VERSION 5.8 ;
BUSBITCHARS "[]" ;
DIVIDERCHAR "/" ;
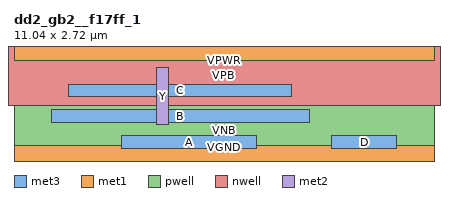
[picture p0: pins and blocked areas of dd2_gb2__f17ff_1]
MACRO dd2_gb2__f17ff_1
  CLASS CORE ;
  ORIGIN 0 0 ;
  SIZE 11.040 BY 2.720 ;
  SYMMETRY X Y ;
  SITE unithd ;
  PIN A
    DIRECTION INPUT ;
    USE SIGNAL ;
    ANTENNAGATEAREA 0.426000 ;
    PORT
      LAYER met3 ;
        RECT 2.825 0.175 6.375 0.505 ;
    END
  END A
  PIN B
    DIRECTION INPUT ;
    USE SIGNAL ;
    ANTENNAGATEAREA 0.426000 ;
    PORT
      LAYER met3 ;
        RECT 0.985 0.855 7.755 1.185 ;
    END
  END B
  PIN C
    DIRECTION INPUT ;
    USE SIGNAL ;
    ANTENNAGATEAREA 0.213000 ;
    PORT
      LAYER met3 ;
        RECT 1.445 1.535 7.295 1.865 ;
    END
  END C
  PIN D
    DIRECTION INPUT ;
    USE SIGNAL ;
    ANTENNAGATEAREA 0.213000 ;
    PORT
      LAYER met3 ;
        RECT 8.345 0.175 10.055 0.505 ;
    END
  END D
  PIN VGND
    DIRECTION INOUT ;
    USE GROUND ;
    SHAPE ABUTMENT ;
    PORT
      LAYER met1 ;
        RECT 0.000 -0.240 11.040 0.240 ;
    END
  END VGND
  PIN VNB
    DIRECTION INOUT ;
    USE GROUND ;
    PORT
      LAYER pwell ;
        RECT 0.000 0.000 11.040 1.305 ;
    END
  END VNB
  PIN VPB
    DIRECTION INOUT ;
    USE POWER ;
    PORT
      LAYER nwell ;
        RECT -0.190 1.305 11.230 2.910 ;
    END
  END VPB
  PIN VPWR
    DIRECTION INOUT ;
    USE POWER ;
    SHAPE ABUTMENT ;
    PORT
      LAYER met1 ;
        RECT 0.000 2.480 11.040 2.960 ;
    END
  END VPWR
  PIN Y
    DIRECTION OUTPUT ;
    USE SIGNAL ;
    ANTENNADIFFAREA 2.635800 ;
    PORT
      LAYER met2 ;
        RECT 3.750 0.790 4.070 2.305 ;
    END
  END Y
  OBS
    LAYER li1 ;
      RECT 0.000 -0.085 11.040 0.085 ;
      RECT 0.605 0.085 0.775 0.565 ;
      RECT 3.365 0.085 3.535 0.565 ;
      RECT 1.905 0.255 2.235 0.710 ;
      RECT 6.505 0.255 6.835 0.710 ;
      RECT 7.885 0.255 8.215 0.710 ;
      RECT 8.805 0.255 9.135 0.710 ;
      RECT 10.185 0.255 10.515 0.710 ;
      RECT 1.065 0.380 1.235 1.075 ;
      RECT 0.945 1.075 1.275 1.245 ;
      RECT 2.905 0.380 3.075 1.075 ;
      RECT 2.785 1.075 3.115 1.245 ;
      RECT 4.285 0.380 4.455 1.075 ;
      RECT 4.165 1.075 4.495 1.245 ;
      RECT 5.665 0.380 5.835 1.075 ;
      RECT 5.545 1.075 5.875 1.245 ;
      RECT 7.045 0.380 7.215 1.075 ;
      RECT 6.925 1.075 7.255 1.245 ;
      RECT 9.805 0.380 9.975 1.075 ;
      RECT 9.685 1.075 10.015 1.245 ;
      RECT 1.485 1.075 1.815 1.245 ;
      RECT 1.525 1.245 1.695 2.340 ;
      RECT 3.325 1.075 3.655 1.245 ;
      RECT 3.365 1.245 3.535 2.340 ;
      RECT 4.705 1.075 5.035 1.245 ;
      RECT 4.745 1.245 4.915 2.340 ;
      RECT 6.085 1.075 6.415 1.245 ;
      RECT 6.125 1.245 6.295 2.340 ;
      RECT 7.465 1.075 7.795 1.245 ;
      RECT 7.505 1.245 7.675 2.340 ;
      RECT 8.385 1.075 8.715 1.245 ;
      RECT 8.425 1.245 8.595 2.340 ;
      RECT 2.365 1.505 2.695 2.465 ;
      RECT 3.745 1.505 4.075 2.465 ;
      RECT 5.125 1.505 5.455 2.465 ;
      RECT 9.265 1.505 9.595 2.465 ;
      RECT 0.605 1.495 0.775 2.635 ;
      RECT 7.965 1.495 8.135 2.635 ;
      RECT 0.000 2.635 11.040 2.805 ;
    LAYER met1 ;
      RECT 1.005 0.380 1.295 0.710 ;
      RECT 1.905 0.380 2.235 0.710 ;
      RECT 2.845 0.380 3.135 0.710 ;
      RECT 4.225 0.380 4.515 0.710 ;
      RECT 5.605 0.380 5.895 0.710 ;
      RECT 6.505 0.380 6.835 0.710 ;
      RECT 6.985 0.380 7.275 0.710 ;
      RECT 7.885 0.380 8.215 0.710 ;
      RECT 9.745 0.380 10.035 0.710 ;
      RECT 10.185 0.380 10.515 0.710 ;
      RECT 8.805 0.380 9.135 0.710 ;
      RECT 3.750 0.790 4.070 0.850 ;
      RECT 8.810 0.710 9.130 0.850 ;
      RECT 9.270 0.790 9.590 0.850 ;
      RECT 3.745 0.850 9.595 0.990 ;
      RECT 3.750 0.990 4.070 1.050 ;
      RECT 8.810 0.990 9.130 1.050 ;
      RECT 9.270 0.990 9.590 1.050 ;
      RECT 2.370 1.230 2.690 1.290 ;
      RECT 5.130 1.230 5.450 1.290 ;
      RECT 2.365 1.290 5.455 1.430 ;
      RECT 2.370 1.430 2.690 1.490 ;
      RECT 5.130 1.430 5.450 1.490 ;
      RECT 6.510 1.230 6.830 1.290 ;
      RECT 10.190 1.230 10.510 1.290 ;
      RECT 6.505 1.290 10.515 1.430 ;
      RECT 6.510 1.430 6.830 1.490 ;
      RECT 10.190 1.430 10.510 1.490 ;
      RECT 1.910 1.670 2.230 1.730 ;
      RECT 7.890 1.670 8.210 1.730 ;
      RECT 1.905 1.730 8.215 1.870 ;
      RECT 1.910 1.870 2.230 1.930 ;
      RECT 7.890 1.870 8.210 1.930 ;
      RECT 1.465 2.010 1.755 2.340 ;
      RECT 2.365 2.010 2.695 2.340 ;
      RECT 3.305 2.010 3.595 2.340 ;
      RECT 3.745 2.010 4.075 2.340 ;
      RECT 4.685 2.010 4.975 2.340 ;
      RECT 5.125 2.010 5.455 2.340 ;
      RECT 6.065 2.010 6.355 2.340 ;
      RECT 7.445 2.010 7.735 2.340 ;
      RECT 8.365 2.010 8.655 2.340 ;
      RECT 9.265 2.010 9.595 2.340 ;
    LAYER met2 ;
      RECT 2.850 0.155 3.130 0.210 ;
      RECT 2.830 0.210 3.150 0.675 ;
      RECT 5.610 0.155 5.890 0.210 ;
      RECT 5.590 0.210 5.910 0.675 ;
      RECT 9.750 0.155 10.030 0.210 ;
      RECT 9.730 0.210 10.050 0.675 ;
      RECT 8.810 0.415 9.130 1.050 ;
      RECT 0.990 0.415 1.310 1.150 ;
      RECT 1.010 1.150 1.290 1.205 ;
      RECT 4.210 0.415 4.530 1.150 ;
      RECT 4.230 1.150 4.510 1.205 ;
      RECT 6.510 0.415 6.830 1.490 ;
      RECT 10.190 0.415 10.510 1.490 ;
      RECT 6.970 0.415 7.290 1.830 ;
      RECT 6.990 1.830 7.270 1.885 ;
      RECT 1.910 0.415 2.230 1.930 ;
      RECT 7.890 0.415 8.210 1.930 ;
      RECT 1.470 1.515 1.750 1.570 ;
      RECT 1.450 1.570 1.770 2.305 ;
      RECT 2.370 1.230 2.690 2.305 ;
      RECT 3.310 0.835 3.590 0.890 ;
      RECT 3.290 0.890 3.610 2.305 ;
      RECT 4.690 0.155 4.970 0.210 ;
      RECT 4.670 0.210 4.990 2.305 ;
      RECT 5.130 1.230 5.450 2.305 ;
      RECT 6.070 0.155 6.350 0.210 ;
      RECT 6.050 0.210 6.370 2.305 ;
      RECT 7.450 0.835 7.730 0.890 ;
      RECT 7.430 0.890 7.750 2.305 ;
      RECT 8.370 0.155 8.650 0.210 ;
      RECT 8.350 0.210 8.670 2.305 ;
      RECT 9.270 0.790 9.590 2.305 ;
  END
END dd2_gb2__f17ff_1
END LIBRARY
